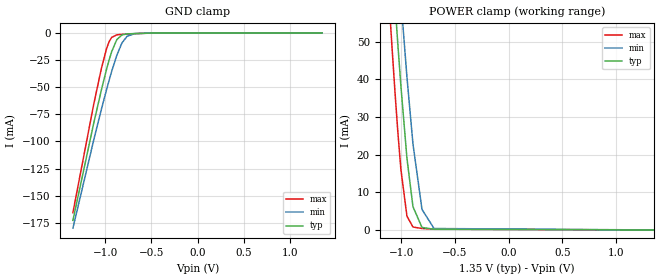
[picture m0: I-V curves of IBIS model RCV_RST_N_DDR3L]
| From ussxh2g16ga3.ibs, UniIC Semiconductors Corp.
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|   Model RCV_RST_N_DDR3L
[Model] RCV_RST_N_DDR3L
Model_type Input
Vinl =  0.540V
Vinh =  0.810V
C_comp   0.725pF   0.725pF   0.725pF
[Model Spec]
Vinh   0.810V   0.776V   0.860V
Vinl   0.540V   0.506V   0.590V
[Temperature Range]   25.000   95.000   -40.000
[Voltage Range]   1.350V   1.283V   1.450V
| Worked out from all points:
|   GND clamp passes 1 mA (typ) near -0.77 V on its own axis
|   POWER clamp passes 1 mA (typ) near -0.82 V on its own axis
[GND_clamp]
|Voltage   I(typ)   I(min)   I(max)
-1.35V    -172.8mA   -179.9mA   -165.6mA
-1.126V   -83.84mA   -99.28mA   -66.45mA
-1.042V   -52.75mA   -70.63mA   -32.99mA
-986mV    -33.67mA   -52.44mA   -14.65mA
-958mV    -25.01mA   -43.77mA   -8.113mA
-930mV    -17.28mA   -35.47mA   -4.15mA
-874mV    -6.141mA   -20.55mA   -1.759mA
-818mV    -1.856mA   -9.196mA   -1.325mA
-762mV    -946uA     -3.027mA   -1.066mA
-678mV    -590.6uA   -657uA     -726.8uA
-510mV    -182.2uA   -145.1uA   -204.8uA
1.35V     0A         0A         0A
[POWER_clamp]
|Voltage   I(typ)   I(min)   I(max)
-1.35V    193.8mA    208.2mA    178.6mA
-1.142V   97mA       117.7mA    74.79mA
-1.114V   84.56mA    105.9mA    61.67mA
-1.086V   72.37mA    94.37mA    48.99mA
-1.058V   60.5mA     82.99mA    36.93mA
-1.03V    49.05mA    71.85mA    25.78mA
-1.002V   38.16mA    61.01mA    16.03mA
-946mV    19.06mA    40.6mA     3.668mA
-890mV    6.184mA    22.84mA    784uA
-806mV    668.8uA    5.465mA    387.6uA
-694mV    183.7uA    385.9uA    217.8uA
1.35V     0A         0A         0A
